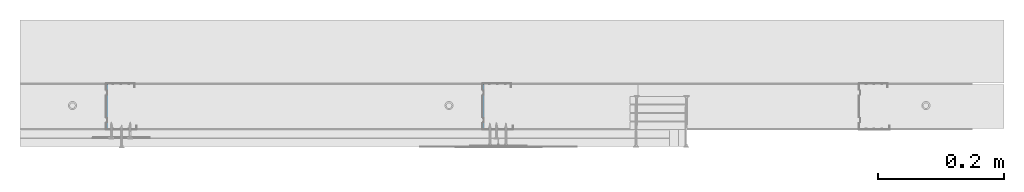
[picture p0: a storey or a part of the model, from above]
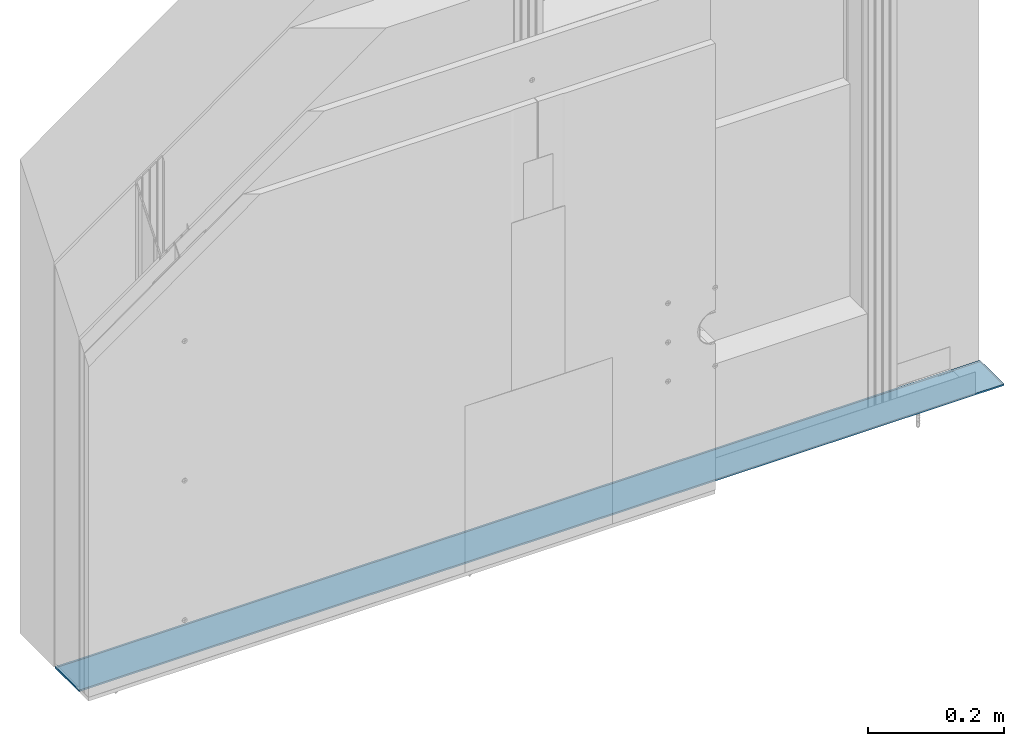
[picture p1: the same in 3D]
Properties of the parts of a building model (IFC2X3)

# File
Description: ViewDefinition [CoordinationView]
Time: 2022-01-19T14:13:05
Made in: SketchUp Pro 2015

# IfcProject, Default Project
Description: Description of Default Project

# IfcSite, Default Site
Description: Description of Default Site; RefLatitude: 24, 28, 0; RefLongitude: 54, 25, 0; RefElevation: 10 mm

# IfcBuilding, Default Building
Description: Description of Default Building

# IfcBuildingStorey, Default Building Storey
In: Default Building
Description: Description of Default Building Storey; Elevation: 0 mm

# IfcWall (55)
In: Default Building Storey
Description: Description of Object
Name
6 x Kołek rozporowy min. fi 6
Profil RIGIPS UW75 ULTRASTIL®
2 x Taśma uszczelniająca piankowa RIGIPS
3 x Profil RIGIPS CW75 ULTRASTIL® | TempShadowInfo - City: Boulder (CO); Country: USA; Latitude: 40.017; Longitude: 40.017-105.283; NorthAngle: 40.017-105.2830; TZOffset: 40.017-105.2830-7
3 x Wełna mineralna szklana lub skalna ISOVER
6 x Wkręt RIGIPS TN 25
9 x Wkręt RIGIPS TN 35
3 x Dedykowana masa szpachlowa Rigips - konstrukcyjna
Taśma spoinowa RIGIPS
8 x Płyta gipsowo-kartonowa RIGIPS PRO (4PRO™)
Dedykowana masa szpachlowa Rigips - wykończeniowa
5 x Wkręt RIGIPS TN 70
PUSZKA
5 x Wkręt RIGIPS TN 45
ŚCIANA
